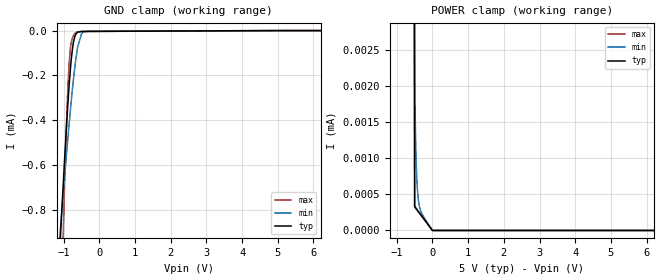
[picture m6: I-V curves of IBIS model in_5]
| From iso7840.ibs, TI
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|   in_5 Model
[Model]   in_5
Model_type   Input
Vinl = 1.5
Vinh = 3.5
|   typ   min   max
|   (nom PVT)   (fast PVT)   (slow PVT)
C_comp   3.281e-15   3.281e-15   3.455e-14
[Model spec]
|subparameter
Vinl   1.5   1.35   1.65
Vinh   3.5   3.15   3.85
| Where nom  PVT is Nominal Process, 5V, 27C
|   Fast PVT is Strong Process,  5.5V, -55C
|   Slow PVT is Weak Process,   4.5V, 150C
[Voltage Range]   5   4.5   5.5
|Ambient Temperature   25   125   -55
|Junction Temperature
[Temperature Range]   27   150   -55
[Power Clamp Reference]   5   4.5   5.5
[GND Clamp Reference]   0   0   0
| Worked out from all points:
|   GND clamp passes 1 mA (typ) near -1.12 V on its own axis
[GND Clamp]
|   Voltage   I(typ)   I(min)   I(max)
-5V       -13.99mA   -9.044mA   -29.25mA
-1.112V   -984.6uA   -924.8uA   -1.503mA
-1.062V   -832.2uA   -825.1uA   -1.194mA
-974mV    -573.5uA   -653.1uA   -684.8uA
-908mV    -392.7uA   -527.9uA   -356.7uA
-850mV    -250.8uA   -421.9uA   -151.8uA
-809mV    -166.1uA   -350.2uA   -74.38uA
-740mV    -65.1uA    -237.9uA   -26.95uA
-608mV    -7.374uA   -73.42uA   -5.426uA
-500mV    -3.903uA   -14.37uA   -3.931uA
-338mV    -3.55uA    -3.864uA   -3.762uA
10V       0A         0A         0A
[POWER Clamp]
|   Voltage   I(typ)   I(min)   I(max)
-5V       185.5mA    66.86mA    305.6mA
-1.007V   213.6uA    173.9uA    305uA
-500mV    338.3nA    2.124uA    322.2nA
-482mV    323.5nA    1.505uA    310.6nA
-473mV    316.7nA    1.273uA    304.8nA
-459.5mV  306.8nA    1.002uA    296.1nA
-432.5mV  288nA      655.7nA    278.7nA
-396.5mV  263.7nA    427.3nA    255.5nA
-360.5mV  239.7nA    320.4nA    232.3nA
-306.5mV  203.8nA    241.2nA    197.5nA
-500uV    0A         0A         0A
10V       0A         0A         0A
